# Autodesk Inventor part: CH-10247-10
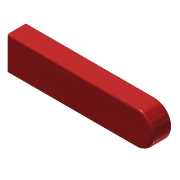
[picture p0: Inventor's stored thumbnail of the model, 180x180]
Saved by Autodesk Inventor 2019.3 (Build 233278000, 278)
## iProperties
Created: 2012-09
Part Number: CH-10247-10
Material: Ogólny
Document SubType Name: Modeling
Designer: CADENGINEERING4
Density: 1 g/cm^3
Appearance: Domyślna
Author: CADENGINEERING4
Revision Number: ÈÎºÎ
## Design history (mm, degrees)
feature "Ô²½Ç1"
node "Bryła1"
